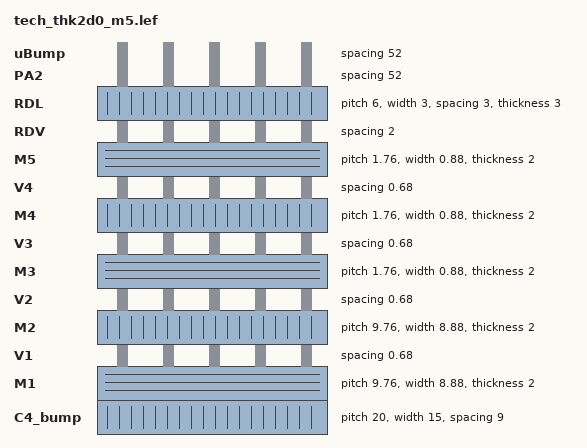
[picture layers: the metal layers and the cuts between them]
VERSION 5.7 ;
BUSBITCHARS "[]" ;
DIVIDERCHAR "/" ;

PROPERTYDEFINITIONS
  LAYER LEF58_TYPE STRING "MAXVIASTACK 2 NOSINGLE RANGE M1 M5 ;" ;
END PROPERTYDEFINITIONS

UNITS
  DATABASE MICRONS 4000 ;
END UNITS
MANUFACTURINGGRID 0.00025 ;

SITE cxm3site
    SYMMETRY y  ;
    CLASS core  ;
    SIZE 47.5 BY 50.32 ;
END cxm3site

LAYER OVERLAP
  TYPE OVERLAP ;
END OVERLAP

LAYER BORD
   TYPE OVERLAP ;
END BORD

LAYER BORD_mark31
   TYPE OVERLAP ;
END BORD_mark31

LAYER BORD_mark32
   TYPE OVERLAP ;
END BORD_mark32

LAYER BORD_mark33
   TYPE OVERLAP ;
END BORD_mark33

LAYER BORD_mark34
   TYPE OVERLAP ;
END BORD_mark34

LAYER BORD_mark109
   TYPE OVERLAP ;
END BORD_mark109

LAYER BORD_mark110
   TYPE OVERLAP ;
END BORD_mark110

LAYER BORD_mark111
   TYPE OVERLAP ;
END BORD_mark111

LAYER BORD_mark116
   TYPE OVERLAP ;
END BORD_mark116

LAYER C4_bump   
   TYPE ROUTING ;
   DIRECTION VERTICAL ;
   WIDTH  15.0 ;
   PITCH  20.0 ;
   SPACING 9.0 ;
END C4_bump

LAYER TSV  # TSV cut layer between M1 & C4_bump 
   TYPE CUT ;
   SPACING 8.0 LAYER OVERLAP ;
END TSV

LAYER M1
  TYPE ROUTING ;
  DIRECTION HORIZONTAL ;
  PITCH 9.76 9.76 ;
  WIDTH 8.88 ;
  OFFSET 0.88 0.88 ;
  AREA 4 ;
  SPACINGTABLE 
    PARALLELRUNLENGTH 0.00 1.50 4.50
      WIDTH 0.00      0.88 0.88 0.88
      WIDTH 1.50      1.00 1.00 1.00
      WIDTH 4.50      1.80 1.80 1.80 ;
  MAXWIDTH 12 ;
  RESISTANCE RPERSQ 0.01 ;
  THICKNESS 2.0 ;
  MINIMUMDENSITY 30 ;
  MAXIMUMDENSITY 75 ;
  DENSITYCHECKWINDOW 200 200 ;
  DENSITYCHECKSTEP 50 ;
END M1

LAYER V1
  TYPE CUT ;
  SPACING 0.68 ;
  SPACING 1.08 ADJACENTCUTS 3 WITHIN 1.1 ;
  ENCLOSURE BELOW 0.08 0.08 ;
  ENCLOSURE ABOVE 0.08 0.08 ;
  ENCLOSURE BELOW 0.37 0.37 WIDTH 5.0 ;
  ENCLOSURE ABOVE 0.37 0.37 WIDTH 5.0 ;
END V1

LAYER M2
  TYPE ROUTING ;
  DIRECTION VERTICAL ;
  PITCH 9.76 9.76 ;
  WIDTH 8.88 ;
  OFFSET 0.88 0.88 ;
  AREA 4 ;
  SPACINGTABLE 
    PARALLELRUNLENGTH 0.00 1.50 4.50
      WIDTH 0.00      0.88 0.88 0.88
      WIDTH 1.50      1.00 1.00 1.00
      WIDTH 4.50      1.80 1.80 1.80 ;
  MAXWIDTH 12 ;
  RESISTANCE RPERSQ 0.01 ;
  THICKNESS 2.0 ;
  MINIMUMDENSITY 30 ;
  MAXIMUMDENSITY 75 ;
  DENSITYCHECKWINDOW 200 200 ;
  DENSITYCHECKSTEP 50 ;
END M2

LAYER V2
  TYPE CUT ;
  SPACING 0.68 ;
  SPACING 1.08 ADJACENTCUTS 3 WITHIN 1.1 ;
  ENCLOSURE BELOW 0.08 0.08 ;
  ENCLOSURE ABOVE 0.08 0.08 ;
  ENCLOSURE BELOW 0.37 0.37 WIDTH 5.0 ;
  ENCLOSURE ABOVE 0.37 0.37 WIDTH 5.0 ;
END V2

LAYER M3
  TYPE ROUTING ;
  DIRECTION HORIZONTAL ;
  PITCH 1.76 1.76 ;
  WIDTH 0.88 ;
  OFFSET 0.88 0.88 ;
  AREA 4 ;
  SPACINGTABLE 
    PARALLELRUNLENGTH 0.00 1.50 4.50
      WIDTH 0.00      0.88 0.88 0.88
      WIDTH 1.50      1.00 1.00 1.00
      WIDTH 4.50      1.80 1.80 1.80 ;
  MAXWIDTH 12 ;
  RESISTANCE RPERSQ 0.01 ;
  THICKNESS 2.0 ;
  MINIMUMDENSITY 30 ;
  MAXIMUMDENSITY 75 ;
  DENSITYCHECKWINDOW 200 200 ;
  DENSITYCHECKSTEP 50 ;
END M3

LAYER V3
  TYPE CUT ;
  SPACING 0.68 ;
  SPACING 1.08 ADJACENTCUTS 3 WITHIN 1.1 ;
  ENCLOSURE BELOW 0.08 0.08 ;
  ENCLOSURE ABOVE 0.08 0.08 ;
  ENCLOSURE BELOW 0.37 0.37 WIDTH 5.0 ;
  ENCLOSURE ABOVE 0.37 0.37 WIDTH 5.0 ;
END V3

LAYER M4
  TYPE ROUTING ;
  DIRECTION VERTICAL ;
  PITCH 1.76 1.76 ;
  WIDTH 0.88 ;
  OFFSET 0.88 0.88 ;
  AREA 4 ;
  SPACINGTABLE 
    PARALLELRUNLENGTH 0.00 1.50 4.50
      WIDTH 0.00      0.88 0.88 0.88
      WIDTH 1.50      1.00 1.00 1.00
      WIDTH 4.50      1.80 1.80 1.80 ;
  MAXWIDTH 12 ;
  RESISTANCE RPERSQ 0.01 ;
  THICKNESS 2.0 ;
  MINIMUMDENSITY 30 ;
  MAXIMUMDENSITY 75 ;
  DENSITYCHECKWINDOW 200 200 ;
  DENSITYCHECKSTEP 50 ;
END M4

LAYER V4
  TYPE CUT ;
  SPACING 0.68 ;
  SPACING 1.08 ADJACENTCUTS 3 WITHIN 1.1 ;
  ENCLOSURE BELOW 0.08 0.08 ;
  ENCLOSURE ABOVE 0.08 0.08 ;
  ENCLOSURE BELOW 0.37 0.37 WIDTH 5.0 ;
  ENCLOSURE ABOVE 0.37 0.37 WIDTH 5.0 ;
END V4

LAYER M5
  TYPE ROUTING ;
  DIRECTION HORIZONTAL ;
  PITCH 1.76 1.76 ;
  WIDTH 0.88 ;
  OFFSET 0.88 0.88 ;
  AREA 4 ;
  SPACINGTABLE 
    PARALLELRUNLENGTH 0.00 1.50 4.50
      WIDTH 0.00      0.88 0.88 0.88
      WIDTH 1.50      1.00 1.00 1.00
      WIDTH 4.50      1.80 1.80 1.80 ;
  MAXWIDTH 12 ;
  RESISTANCE RPERSQ 0.01 ;
  THICKNESS 2.0 ;
  MINIMUMDENSITY 30 ;
  MAXIMUMDENSITY 75 ;
  DENSITYCHECKWINDOW 200 200 ;
  DENSITYCHECKSTEP 50 ;
END M5

LAYER RDV
  TYPE CUT ;
  SPACING 2.0 ;
END RDV

LAYER RDL
  TYPE ROUTING ;
  DIRECTION VERTICAL ;
  WIDTH 3 ;
  SPACING 3 ;
  PITCH   6 ;
  OFFSET  2 ;
  RESISTANCE RPERSQ 0.012 ;
  THICKNESS 3.0 ;
END RDL

LAYER PA2
  TYPE CUT ;
  SPACING 52 ;
  PROPERTY LEF58_TYPE "TYPE PASSIVATION ;" ;
END PA2

LAYER uBump
  TYPE  CUT ;
  SPACING  52 ;
  PROPERTY LEF58_TYPE "TYPE PASSIVATION ;" ;
END uBump   

VIA VIA_TSV DEFAULT
    RESISTANCE 0.15 ;
    LAYER C4_bump ;
          RECT -0.44 -0.44 0.44 0.44 ; 
    LAYER TSV ;
          RECT -0.36 -0.36 0.36 0.36 ;
    LAYER M1 ;
          RECT -0.44 -0.44 0.44 0.44 ; 
END VIA_TSV

VIA VIA1_1cut DEFAULT
    RESISTANCE 0.15 ;
    LAYER M1 ;
          RECT -0.44 -0.44 0.44 0.44 ; 
    LAYER V1 ;
          RECT -0.36 -0.36 0.36 0.36 ;
    LAYER M2 ;
          RECT -0.44 -0.44 0.44 0.44 ; 
END VIA1_1cut

VIA VIA1_2cut DEFAULT 
    RESISTANCE 0.075 ;
    LAYER M1 ;
          RECT -1.14 -0.44 1.14 0.44 ; 
    LAYER V1 ;
          RECT -1.06 -0.36 -0.34 0.36 ;
          RECT  0.34 -0.36  1.06 0.36 ;
    LAYER M2 ;
          RECT -1.14 -0.44 1.14 0.44 ; 
END VIA1_2cut

VIA VIA1_4cut DEFAULT 
    RESISTANCE 0.0375 ;
    LAYER M1 ;
          RECT -1.225 -1.225 1.225 1.225 ; 
    LAYER V1 ;
          RECT -1.145 -1.145 -0.425 -0.425 ;
          RECT -1.145  0.425 -0.425  1.145 ;
          RECT  0.425 -1.145  1.145 -0.425 ;
          RECT  0.425  0.425  1.145  1.145 ;
    LAYER M2 ;
          RECT -1.225 -1.225 1.225 1.225 ; 
END VIA1_4cut

VIA VIA2_1cut DEFAULT
    RESISTANCE 0.15 ;
    LAYER M2 ;
          RECT -0.44 -0.44 0.44 0.44 ; 
    LAYER V2 ;
          RECT -0.36 -0.36 0.36 0.36 ;
    LAYER M3 ;
          RECT -0.44 -0.44 0.44 0.44 ; 
END VIA2_1cut

VIA VIA2_2cut DEFAULT 
    RESISTANCE 0.075 ;
    LAYER M2 ;
          RECT -1.14 -0.44 1.14 0.44 ; 
    LAYER V2 ;
          RECT -1.06 -0.36 -0.34 0.36 ;
          RECT  0.34 -0.36  1.06 0.36 ;
    LAYER M3 ;
          RECT -1.14 -0.44 1.14 0.44 ; 
END VIA2_2cut

VIA VIA2_4cut DEFAULT 
    RESISTANCE 0.0375 ;
    LAYER M2 ;
          RECT -1.225 -1.225 1.225 1.225 ; 
    LAYER V2 ;
          RECT -1.145 -1.145 -0.425 -0.425 ;
          RECT -1.145  0.425 -0.425  1.145 ;
          RECT  0.425 -1.145  1.145 -0.425 ;
          RECT  0.425  0.425  1.145  1.145 ;
    LAYER M3 ;
          RECT -1.225 -1.225 1.225 1.225 ; 
END VIA2_4cut

VIA VIA3_1cut DEFAULT
    RESISTANCE 0.15 ;
    LAYER M3 ;
          RECT -0.44 -0.44 0.44 0.44 ; 
    LAYER V3 ;
          RECT -0.36 -0.36 0.36 0.36 ;
    LAYER M4 ;
          RECT -0.44 -0.44 0.44 0.44 ; 
END VIA3_1cut

VIA VIA3_2cut DEFAULT 
    RESISTANCE 0.075 ;
    LAYER M3 ;
          RECT -1.14 -0.44 1.14 0.44 ; 
    LAYER V3 ;
          RECT -1.06 -0.36 -0.34 0.36 ;
          RECT  0.34 -0.36  1.06 0.36 ;
    LAYER M4 ;
          RECT -1.14 -0.44 1.14 0.44 ; 
END VIA3_2cut

VIA VIA3_4cut DEFAULT 
    RESISTANCE 0.0375 ;
    LAYER M3 ;
          RECT -1.225 -1.225 1.225 1.225 ; 
    LAYER V3 ;
          RECT -1.145 -1.145 -0.425 -0.425 ;
          RECT -1.145  0.425 -0.425  1.145 ;
          RECT  0.425 -1.145  1.145 -0.425 ;
          RECT  0.425  0.425  1.145  1.145 ;
    LAYER M4 ;
          RECT -1.225 -1.225 1.225 1.225 ; 
END VIA3_4cut

VIA VIA4_1cut DEFAULT
    RESISTANCE 0.15 ;
    LAYER M4 ;
          RECT -0.44 -0.44 0.44 0.44 ; 
    LAYER V4 ;
          RECT -0.36 -0.36 0.36 0.36 ;
    LAYER M5 ;
          RECT -0.44 -0.44 0.44 0.44 ; 
END VIA4_1cut

VIA VIA4_2cut DEFAULT 
    RESISTANCE 0.075 ;
    LAYER M4 ;
          RECT -1.14 -0.44 1.14 0.44 ; 
    LAYER V4 ;
          RECT -1.06 -0.36 -0.34 0.36 ;
          RECT  0.34 -0.36  1.06 0.36 ;
    LAYER M5 ;
          RECT -1.14 -0.44 1.14 0.44 ; 
END VIA4_2cut

VIA VIA4_4cut DEFAULT 
    RESISTANCE 0.0375 ;
    LAYER M4 ;
          RECT -1.225 -1.225 1.225 1.225 ; 
    LAYER V4 ;
          RECT -1.145 -1.145 -0.425 -0.425 ;
          RECT -1.145  0.425 -0.425  1.145 ;
          RECT  0.425 -1.145  1.145 -0.425 ;
          RECT  0.425  0.425  1.145  1.145 ;
    LAYER M5 ;
          RECT -1.225 -1.225 1.225 1.225 ; 
END VIA4_4cut

VIA VIA_RDV_1cut DEFAULT 
    RESISTANCE 0.072 ;
    LAYER M5 ;
          RECT -2.00 -2.00 2.00 2.00 ; 
    LAYER RDV ;
          RECT -1.50 -1.50 1.50 1.50 ;
    LAYER RDL ;
          RECT -2.00 -2.00 2.00 2.00 ; 
END VIA_RDV_1cut


VIARULE GENV1 GENERATE
  LAYER M1 ;
    ENCLOSURE 0.37 0.37 ;
    WIDTH 0.88 TO 14 ;
  LAYER M2 ;
    ENCLOSURE 0.08 0.08 ;
  LAYER V1 ;
    RECT -0.36 -0.36 0.36 0.36 ;
END GENV1

VIARULE GENV2 GENERATE
  LAYER M2 ;
    ENCLOSURE 0.08 0.08 ;
  LAYER M3 ;
    ENCLOSURE 0.08 0.08 ;
  LAYER V2 ;
    RECT -0.36 -0.36 0.36 0.36 ;
    SPACING 1.4 BY 1.4 ;
END GENV2

VIARULE GENV3 GENERATE
  LAYER M3 ;
    ENCLOSURE 0.08 0.08 ;
  LAYER M4 ;
    ENCLOSURE 0.08 0.08 ;
  LAYER V3 ;
    RECT -0.36 -0.36 0.36 0.36 ;
    SPACING 1.4 BY 1.4 ;
END GENV3

VIARULE GENV4 GENERATE
  LAYER M4 ;
    ENCLOSURE 0.08 0.08 ;
  LAYER M5 ;
    ENCLOSURE 0.08 0.08 ;
  LAYER V4 ;
    RECT -0.36 -0.36 0.36 0.36 ;
    SPACING 1.4 BY 1.4 ;
END GENV4

VIARULE GENRDV GENERATE
  LAYER M5 ;
    ENCLOSURE 0.5 0.5 ;
  LAYER RDL ;
    ENCLOSURE 0.5 0.5 ;
  LAYER RDV ;
    RECT -1.5 -1.5 1.5 1.5 ;
    SPACING 5 BY 5 ;
END GENRDV

END LIBRARY
